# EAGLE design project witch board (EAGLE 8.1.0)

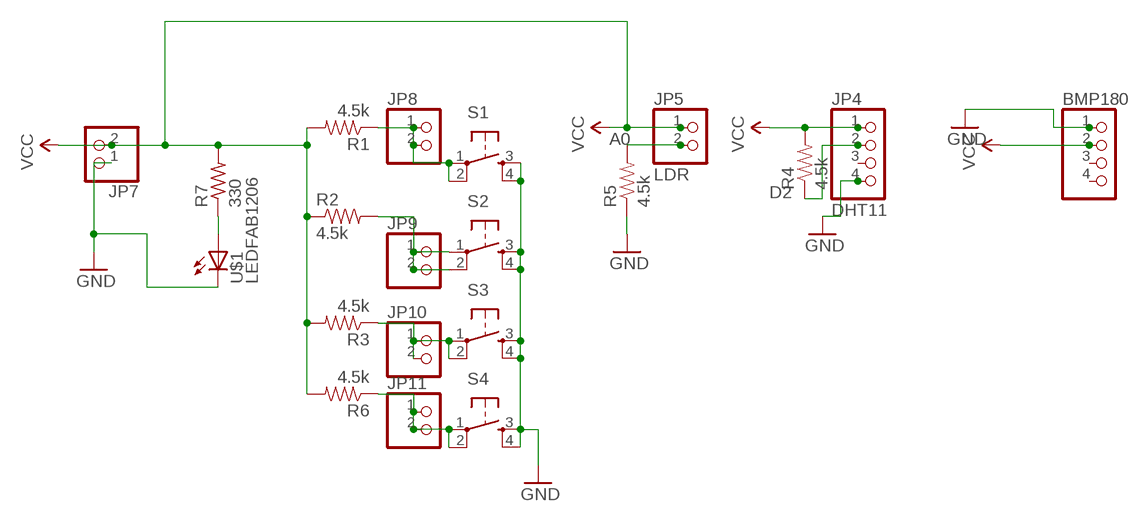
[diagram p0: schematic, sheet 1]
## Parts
BMP180  PINHD-1X4  [1X04]
JP4  DHT11  PINHD-1X4  [1X04]
JP5  LDR  PINHD-1X2  [1X02]
JP7  PINHD-1X2  [1X02]
JP8  PINHD-1X2  [1X02]
JP9  PINHD-1X2  [1X02]
JP10  PINHD-1X2  [1X02]
JP11  PINHD-1X2  [1X02]
R1  4.5k  RESISTOR1206  [1206]
R2  4.5k  RESISTOR1206  [1206]
R3  4.5k  RESISTOR1206  [1206]
R4  4.5k  RESISTOR1206  [1206]
R5  4.5k  RESISTOR1206  [1206]
R6  4.5k  RESISTOR1206  [1206]
R7  330  RES-US1206FAB  [R1206FAB]
S1  6MM_SWITCH6MM_SWITCH  [6MM_SWITCH]
S2  6MM_SWITCH6MM_SWITCH  [6MM_SWITCH]
S3  6MM_SWITCH6MM_SWITCH  [6MM_SWITCH]
S4  6MM_SWITCH6MM_SWITCH  [6MM_SWITCH]
U$1  LEDFAB1206  [LED1206FAB]

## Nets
A0: JP5.2 R5.2
D2: JP4.2 R4.1
GND [vcc]: BMP180.1 JP4.4 JP7.1 R5.1 S1.3(S) S1.4(S1) S2.3(S) S2.4(S1) S3.3(S) S3.4(S1) S4.3(S) S4.4(S1) U$1.2(C)
N$1: JP8.1 JP8.2 R1.1 S1.1(P) S1.2(P1)
N$2: JP9.1 JP9.2 R2.2 S2.1(P) S2.2(P1)
N$3: JP10.1 JP10.2 R3.1 S3.1(P) S3.2(P1)
N$4: JP11.1 JP11.2 R6.1 S4.1(P) S4.2(P1)
N$5: R7.1 U$1.1(A)
VCC: BMP180.2 JP4.1 JP5.1 JP7.2 R1.2 R2.1 R3.2 R4.2 R6.2 R7.2
Unconnected: BMP180.3 BMP180.4 JP4.3

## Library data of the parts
BMP180 JP4 = pinhead:PINHD-1X4: PIN HEADER
JP5 JP7-JP11 = pinhead:PINHD-1X2: PIN HEADER
R1-R6 = SparkFun:RESISTOR: Resistor
R7 = fab:RES-US: Resistor (US Symbol)
S1-S4 = fab:6MM_SWITCH: OMRON SWITCH
U$1 = fab:LED: LED

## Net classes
0 default: width 0.203 mm
1 vcc: width 0.254 mm

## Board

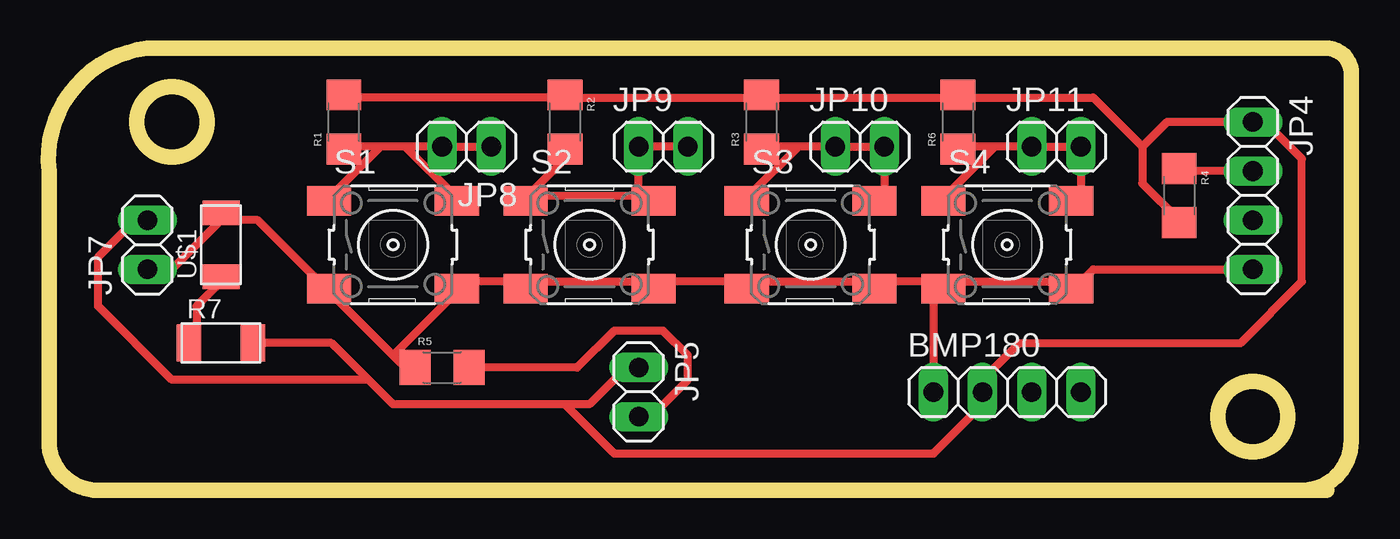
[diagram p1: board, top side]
Size 67.34 x 22.86 mm. Coordinates in mm from the lower left corner, seen from the top.
Outline: 66.07,0 64.8,0
Outline: 64.8,0 2.57,0 arc-90 0.03,2.54 0.03,16.51 arc-90 5.11,22.86 66.07,22.86 arc-90 67.34,21.59 67.34,2.54 arc-90 64.8,0
Outline: circle at 6.38,19.05 radius 1.8
Outline: circle at 62.26,3.81 radius 1.8
Copper layers (1*16): Top 0.035mm / dielectric 1.5mm / Bottom 0.035mm
Design rules "default *": minimum track width 16mil, minimum drill 24mil, track to track 16mil, track to pad 16mil, pad to pad 16mil, via to via 16mil, smd to smd 16mil, copper to edge 40mil, drill to drill 16mil, minimum pad ring 10mil, minimum via ring 8mil, stop-mask expansion 4mil, vias tented up to drill 0mil, thermal gap 10mil

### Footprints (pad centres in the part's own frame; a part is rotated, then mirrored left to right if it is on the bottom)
1X04 = drill 1.016 long: 1 -3.81,0; 2 -1.27,0; 3 1.27,0; 4 3.81,0
1X02 = drill 1.016 long: 1 -1.27,0; 2 1.27,0
1206 = smd 1.6 x 1.8: 1 -1.4,0; 2 1.4,0
R1206FAB = smd 1.27 x 1.905: 1 -1.651,0; 2 1.651,0
6MM_SWITCH = smd 2.286 x 1.524: 1 -3.302,2.286; 2 3.302,2.286; 3 -3.302,-2.286; 4 3.302,-2.286
LED1206FAB = smd 1.27 x 1.905: 1 -1.651,0; 2 1.651,0

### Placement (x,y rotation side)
BMP180  49.56,5.08 0 top
JP4  62.26,15.24 270 top
JP5  30.51,5.08 270 top
JP7  5.11,12.7 90 top
JP8  21.62,17.78 180 top
JP9  31.78,17.78 0 top
JP10  41.94,17.78 0 top
JP11  52.1,17.78 0 top
R1  15.27,19.05 90 top
R2  26.7,19.05 270 top
R3  36.86,19.05 90 top
R4  58.45,15.24 270 top
R5  20.35,6.35 0 top
R6  47.02,19.05 90 top
R7  8.92,7.62 0 top
S1  17.81,12.7 0 top
S2  27.97,12.7 0 top
S3  39.4,12.7 0 top
S4  49.56,12.7 0 top
U$1  8.92,12.7 90 top

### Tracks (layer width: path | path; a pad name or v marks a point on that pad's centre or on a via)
A0
  Top 0.406: R5.2 27.34,6.35 29.24,8.26 31.78,8.26 33.05,6.99 33.05,5.71 31.15,3.81 JP5.2
D2
  Top 0.406: JP4.2 58.45,16.51 R4.1
GND
  Top 0.406: S4.3 45.75,10.79 43.21,10.79 S3.4 42.58,10.79 36.23,10.79 S3.3 35.59,10.79 31.78,10.79 S2.4 31.15,10.79 24.8,10.79 S2.3 24.16,10.79 21.62,10.79 S1.4 20.99,10.16 17.81,6.99 | S4.3 46.39,10.79 52.74,10.79 S4.4 53.37,10.79 54.01,11.43 JP4.4 | BMP180.1 45.75,10.16 S4.3 | 8.92,13.97 6.38,11.43 JP7.1 | 17.81,6.99 14.64,10.16 S1.3 14,10.79 10.83,13.97 8.92,13.97 | 17.81,6.99 18.45,6.35 R5.1 | 8.92,13.97 U$1.2
N$1
  Top 0.406: 18.45,17.78 JP8.2 JP8.1 | 18.45,17.78 17.18,17.78 | 17.18,17.78 15.27,17.78 R1.1 | 17.18,17.78 14.64,15.24 S1.1 | 18.45,17.78 20.99,15.24 S1.2
N$2
  Top 0.406: JP9.2 JP9.1 30.51,15.24 | 24.8,15.24 26.7,17.14 R2.2 | 24.8,15.24 30.51,15.24 | 30.51,15.24 31.15,15.24 S2.2 30.51,15.24 | 24.8,15.24 S2.1
N$3
  Top 0.406: S3.2 43.21,15.24 JP10.2 JP10.1 38.77,17.78 | 38.77,17.78 36.86,17.78 R3.1 | 38.77,17.78 36.23,15.24 S3.1
N$4
  Top 0.406: S4.2 53.37,15.24 JP11.2 JP11.1 48.93,17.78 | 48.93,17.78 47.02,17.78 R6.1 | 48.93,17.78 46.39,15.24 S4.1
N$5
  Top 0.406: R7.1 7.65,7.62 7.65,9.53 8.92,10.79 U$1.1
VCC
  Top 0.406: 56.55,17.78 56.55,15.88 58.45,13.97 R4.2 | 56.55,17.78 57.82,19.05 JP4.1 62.9,19.05 64.8,17.14 64.8,10.79 61.63,7.62 50.2,7.62 48.29,5.71 BMP180.2 48.29,4.45 45.75,1.91 29.24,1.91 26.7,4.45 | 26.7,20.32 15.27,20.32 R1.2 | 26.7,20.32 36.86,20.32 | 26.7,20.32 R2.1 | 36.86,20.32 47.02,20.32 | 36.86,20.32 R3.2 | 56.55,17.78 54.01,20.32 47.02,20.32 | 47.02,20.32 R6.2 | R7.2 14.64,7.62 16.54,5.71 | 16.54,5.71 17.81,4.45 26.7,4.45 | 26.7,4.45 27.97,4.45 29.88,6.35 JP5.1 | JP7.2 4.48,13.97 2.57,12.07 2.57,9.53 6.38,5.71 16.54,5.71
